VERSION 5.7 ;
BUSBITCHARS "[]" ;
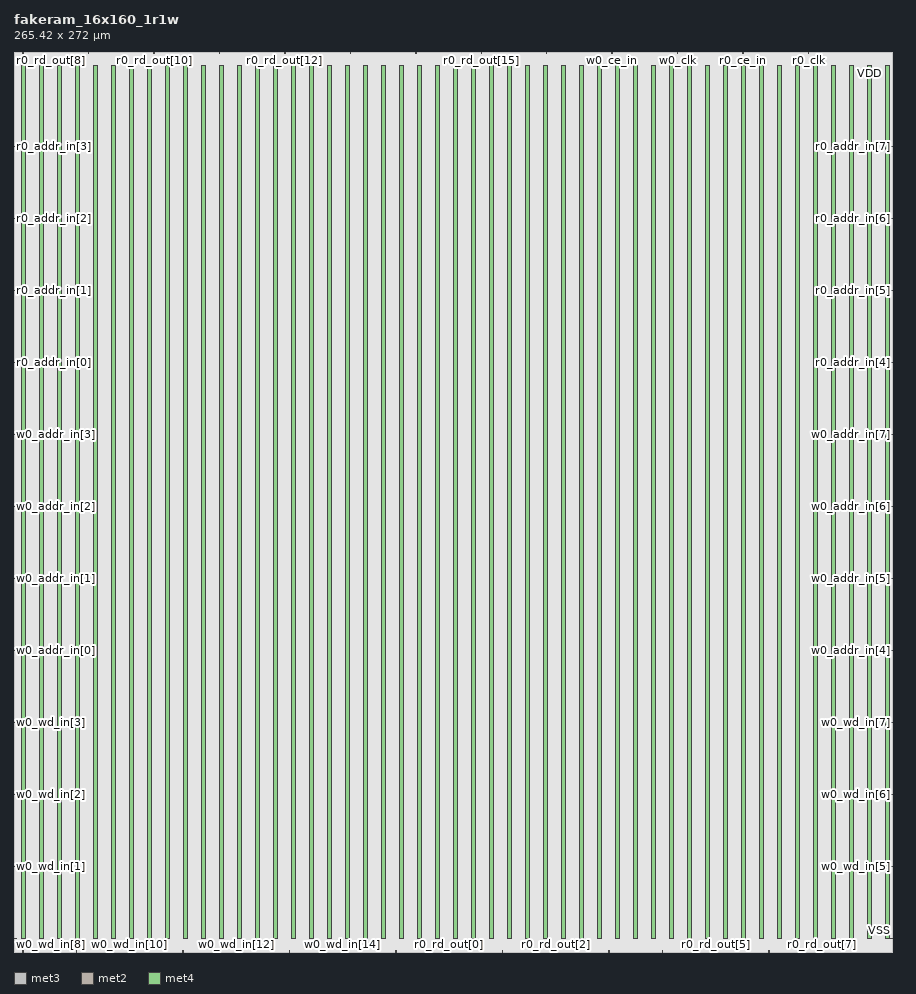
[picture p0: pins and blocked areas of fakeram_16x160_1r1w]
MACRO fakeram_16x160_1r1w
  FOREIGN fakeram_16x160_1r1w 0 0 ;
  SYMMETRY X Y R90 ;
  SIZE 265.420 BY 272.000 ;
  CLASS BLOCK ;
  PIN w0_wd_in[0]
    DIRECTION INPUT ;
    USE SIGNAL ;
    SHAPE ABUTMENT ;
    PORT
      LAYER met3 ;
      RECT 0.000 3.930 0.900 4.230 ;
    END
  END w0_wd_in[0]
  PIN w0_wd_in[1]
    DIRECTION INPUT ;
    USE SIGNAL ;
    SHAPE ABUTMENT ;
    PORT
      LAYER met3 ;
      RECT 0.000 25.690 0.900 25.990 ;
    END
  END w0_wd_in[1]
  PIN w0_wd_in[2]
    DIRECTION INPUT ;
    USE SIGNAL ;
    SHAPE ABUTMENT ;
    PORT
      LAYER met3 ;
      RECT 0.000 47.450 0.900 47.750 ;
    END
  END w0_wd_in[2]
  PIN w0_wd_in[3]
    DIRECTION INPUT ;
    USE SIGNAL ;
    SHAPE ABUTMENT ;
    PORT
      LAYER met3 ;
      RECT 0.000 69.210 0.900 69.510 ;
    END
  END w0_wd_in[3]
  PIN w0_wd_in[4]
    DIRECTION INPUT ;
    USE SIGNAL ;
    SHAPE ABUTMENT ;
    PORT
      LAYER met3 ;
      RECT 264.520 3.930 265.420 4.230 ;
    END
  END w0_wd_in[4]
  PIN w0_wd_in[5]
    DIRECTION INPUT ;
    USE SIGNAL ;
    SHAPE ABUTMENT ;
    PORT
      LAYER met3 ;
      RECT 264.520 25.690 265.420 25.990 ;
    END
  END w0_wd_in[5]
  PIN w0_wd_in[6]
    DIRECTION INPUT ;
    USE SIGNAL ;
    SHAPE ABUTMENT ;
    PORT
      LAYER met3 ;
      RECT 264.520 47.450 265.420 47.750 ;
    END
  END w0_wd_in[6]
  PIN w0_wd_in[7]
    DIRECTION INPUT ;
    USE SIGNAL ;
    SHAPE ABUTMENT ;
    PORT
      LAYER met3 ;
      RECT 264.520 69.210 265.420 69.510 ;
    END
  END w0_wd_in[7]
  PIN w0_wd_in[8]
    DIRECTION INPUT ;
    USE SIGNAL ;
    SHAPE ABUTMENT ;
    PORT
      LAYER met2 ;
      RECT 2.690 0.000 2.830 0.420 ;
    END
  END w0_wd_in[8]
  PIN w0_wd_in[9]
    DIRECTION INPUT ;
    USE SIGNAL ;
    SHAPE ABUTMENT ;
    PORT
      LAYER met2 ;
      RECT 18.790 0.000 18.930 0.420 ;
    END
  END w0_wd_in[9]
  PIN w0_wd_in[10]
    DIRECTION INPUT ;
    USE SIGNAL ;
    SHAPE ABUTMENT ;
    PORT
      LAYER met2 ;
      RECT 34.890 0.000 35.030 0.420 ;
    END
  END w0_wd_in[10]
  PIN w0_wd_in[11]
    DIRECTION INPUT ;
    USE SIGNAL ;
    SHAPE ABUTMENT ;
    PORT
      LAYER met2 ;
      RECT 50.990 0.000 51.130 0.420 ;
    END
  END w0_wd_in[11]
  PIN w0_wd_in[12]
    DIRECTION INPUT ;
    USE SIGNAL ;
    SHAPE ABUTMENT ;
    PORT
      LAYER met2 ;
      RECT 67.090 0.000 67.230 0.420 ;
    END
  END w0_wd_in[12]
  PIN w0_wd_in[13]
    DIRECTION INPUT ;
    USE SIGNAL ;
    SHAPE ABUTMENT ;
    PORT
      LAYER met2 ;
      RECT 83.190 0.000 83.330 0.420 ;
    END
  END w0_wd_in[13]
  PIN w0_wd_in[14]
    DIRECTION INPUT ;
    USE SIGNAL ;
    SHAPE ABUTMENT ;
    PORT
      LAYER met2 ;
      RECT 99.290 0.000 99.430 0.420 ;
    END
  END w0_wd_in[14]
  PIN w0_wd_in[15]
    DIRECTION INPUT ;
    USE SIGNAL ;
    SHAPE ABUTMENT ;
    PORT
      LAYER met2 ;
      RECT 115.390 0.000 115.530 0.420 ;
    END
  END w0_wd_in[15]
  PIN r0_rd_out[0]
    DIRECTION OUTPUT ;
    USE SIGNAL ;
    SHAPE ABUTMENT ;
    PORT
      LAYER met2 ;
      RECT 131.490 0.000 131.630 0.420 ;
    END
  END r0_rd_out[0]
  PIN r0_rd_out[1]
    DIRECTION OUTPUT ;
    USE SIGNAL ;
    SHAPE ABUTMENT ;
    PORT
      LAYER met2 ;
      RECT 147.590 0.000 147.730 0.420 ;
    END
  END r0_rd_out[1]
  PIN r0_rd_out[2]
    DIRECTION OUTPUT ;
    USE SIGNAL ;
    SHAPE ABUTMENT ;
    PORT
      LAYER met2 ;
      RECT 163.690 0.000 163.830 0.420 ;
    END
  END r0_rd_out[2]
  PIN r0_rd_out[3]
    DIRECTION OUTPUT ;
    USE SIGNAL ;
    SHAPE ABUTMENT ;
    PORT
      LAYER met2 ;
      RECT 179.790 0.000 179.930 0.420 ;
    END
  END r0_rd_out[3]
  PIN r0_rd_out[4]
    DIRECTION OUTPUT ;
    USE SIGNAL ;
    SHAPE ABUTMENT ;
    PORT
      LAYER met2 ;
      RECT 195.890 0.000 196.030 0.420 ;
    END
  END r0_rd_out[4]
  PIN r0_rd_out[5]
    DIRECTION OUTPUT ;
    USE SIGNAL ;
    SHAPE ABUTMENT ;
    PORT
      LAYER met2 ;
      RECT 211.990 0.000 212.130 0.420 ;
    END
  END r0_rd_out[5]
  PIN r0_rd_out[6]
    DIRECTION OUTPUT ;
    USE SIGNAL ;
    SHAPE ABUTMENT ;
    PORT
      LAYER met2 ;
      RECT 228.090 0.000 228.230 0.420 ;
    END
  END r0_rd_out[6]
  PIN r0_rd_out[7]
    DIRECTION OUTPUT ;
    USE SIGNAL ;
    SHAPE ABUTMENT ;
    PORT
      LAYER met2 ;
      RECT 244.190 0.000 244.330 0.420 ;
    END
  END r0_rd_out[7]
  PIN r0_rd_out[8]
    DIRECTION OUTPUT ;
    USE SIGNAL ;
    SHAPE ABUTMENT ;
    PORT
      LAYER met2 ;
      RECT 2.690 271.580 2.830 272.000 ;
    END
  END r0_rd_out[8]
  PIN r0_rd_out[9]
    DIRECTION OUTPUT ;
    USE SIGNAL ;
    SHAPE ABUTMENT ;
    PORT
      LAYER met2 ;
      RECT 22.470 271.580 22.610 272.000 ;
    END
  END r0_rd_out[9]
  PIN r0_rd_out[10]
    DIRECTION OUTPUT ;
    USE SIGNAL ;
    SHAPE ABUTMENT ;
    PORT
      LAYER met2 ;
      RECT 42.250 271.580 42.390 272.000 ;
    END
  END r0_rd_out[10]
  PIN r0_rd_out[11]
    DIRECTION OUTPUT ;
    USE SIGNAL ;
    SHAPE ABUTMENT ;
    PORT
      LAYER met2 ;
      RECT 62.030 271.580 62.170 272.000 ;
    END
  END r0_rd_out[11]
  PIN r0_rd_out[12]
    DIRECTION OUTPUT ;
    USE SIGNAL ;
    SHAPE ABUTMENT ;
    PORT
      LAYER met2 ;
      RECT 81.810 271.580 81.950 272.000 ;
    END
  END r0_rd_out[12]
  PIN r0_rd_out[13]
    DIRECTION OUTPUT ;
    USE SIGNAL ;
    SHAPE ABUTMENT ;
    PORT
      LAYER met2 ;
      RECT 101.590 271.580 101.730 272.000 ;
    END
  END r0_rd_out[13]
  PIN r0_rd_out[14]
    DIRECTION OUTPUT ;
    USE SIGNAL ;
    SHAPE ABUTMENT ;
    PORT
      LAYER met2 ;
      RECT 121.370 271.580 121.510 272.000 ;
    END
  END r0_rd_out[14]
  PIN r0_rd_out[15]
    DIRECTION OUTPUT ;
    USE SIGNAL ;
    SHAPE ABUTMENT ;
    PORT
      LAYER met2 ;
      RECT 141.150 271.580 141.290 272.000 ;
    END
  END r0_rd_out[15]
  PIN w0_addr_in[0]
    DIRECTION INPUT ;
    USE SIGNAL ;
    SHAPE ABUTMENT ;
    PORT
      LAYER met3 ;
      RECT 0.000 90.970 0.900 91.270 ;
    END
  END w0_addr_in[0]
  PIN w0_addr_in[1]
    DIRECTION INPUT ;
    USE SIGNAL ;
    SHAPE ABUTMENT ;
    PORT
      LAYER met3 ;
      RECT 0.000 112.730 0.900 113.030 ;
    END
  END w0_addr_in[1]
  PIN w0_addr_in[2]
    DIRECTION INPUT ;
    USE SIGNAL ;
    SHAPE ABUTMENT ;
    PORT
      LAYER met3 ;
      RECT 0.000 134.490 0.900 134.790 ;
    END
  END w0_addr_in[2]
  PIN w0_addr_in[3]
    DIRECTION INPUT ;
    USE SIGNAL ;
    SHAPE ABUTMENT ;
    PORT
      LAYER met3 ;
      RECT 0.000 156.250 0.900 156.550 ;
    END
  END w0_addr_in[3]
  PIN w0_addr_in[4]
    DIRECTION INPUT ;
    USE SIGNAL ;
    SHAPE ABUTMENT ;
    PORT
      LAYER met3 ;
      RECT 264.520 90.970 265.420 91.270 ;
    END
  END w0_addr_in[4]
  PIN w0_addr_in[5]
    DIRECTION INPUT ;
    USE SIGNAL ;
    SHAPE ABUTMENT ;
    PORT
      LAYER met3 ;
      RECT 264.520 112.730 265.420 113.030 ;
    END
  END w0_addr_in[5]
  PIN w0_addr_in[6]
    DIRECTION INPUT ;
    USE SIGNAL ;
    SHAPE ABUTMENT ;
    PORT
      LAYER met3 ;
      RECT 264.520 134.490 265.420 134.790 ;
    END
  END w0_addr_in[6]
  PIN w0_addr_in[7]
    DIRECTION INPUT ;
    USE SIGNAL ;
    SHAPE ABUTMENT ;
    PORT
      LAYER met3 ;
      RECT 264.520 156.250 265.420 156.550 ;
    END
  END w0_addr_in[7]
  PIN r0_addr_in[0]
    DIRECTION INPUT ;
    USE SIGNAL ;
    SHAPE ABUTMENT ;
    PORT
      LAYER met3 ;
      RECT 0.000 178.010 0.900 178.310 ;
    END
  END r0_addr_in[0]
  PIN r0_addr_in[1]
    DIRECTION INPUT ;
    USE SIGNAL ;
    SHAPE ABUTMENT ;
    PORT
      LAYER met3 ;
      RECT 0.000 199.770 0.900 200.070 ;
    END
  END r0_addr_in[1]
  PIN r0_addr_in[2]
    DIRECTION INPUT ;
    USE SIGNAL ;
    SHAPE ABUTMENT ;
    PORT
      LAYER met3 ;
      RECT 0.000 221.530 0.900 221.830 ;
    END
  END r0_addr_in[2]
  PIN r0_addr_in[3]
    DIRECTION INPUT ;
    USE SIGNAL ;
    SHAPE ABUTMENT ;
    PORT
      LAYER met3 ;
      RECT 0.000 243.290 0.900 243.590 ;
    END
  END r0_addr_in[3]
  PIN r0_addr_in[4]
    DIRECTION INPUT ;
    USE SIGNAL ;
    SHAPE ABUTMENT ;
    PORT
      LAYER met3 ;
      RECT 264.520 178.010 265.420 178.310 ;
    END
  END r0_addr_in[4]
  PIN r0_addr_in[5]
    DIRECTION INPUT ;
    USE SIGNAL ;
    SHAPE ABUTMENT ;
    PORT
      LAYER met3 ;
      RECT 264.520 199.770 265.420 200.070 ;
    END
  END r0_addr_in[5]
  PIN r0_addr_in[6]
    DIRECTION INPUT ;
    USE SIGNAL ;
    SHAPE ABUTMENT ;
    PORT
      LAYER met3 ;
      RECT 264.520 221.530 265.420 221.830 ;
    END
  END r0_addr_in[6]
  PIN r0_addr_in[7]
    DIRECTION INPUT ;
    USE SIGNAL ;
    SHAPE ABUTMENT ;
    PORT
      LAYER met3 ;
      RECT 264.520 243.290 265.420 243.590 ;
    END
  END r0_addr_in[7]
  PIN w0_we_in
    DIRECTION INPUT ;
    USE SIGNAL ;
    SHAPE ABUTMENT ;
    PORT
      LAYER met2 ;
      RECT 160.930 271.580 161.070 272.000 ;
    END
  END w0_we_in
  PIN w0_ce_in
    DIRECTION INPUT ;
    USE SIGNAL ;
    SHAPE ABUTMENT ;
    PORT
      LAYER met2 ;
      RECT 180.710 271.580 180.850 272.000 ;
    END
  END w0_ce_in
  PIN w0_clk
    DIRECTION INPUT ;
    USE SIGNAL ;
    SHAPE ABUTMENT ;
    PORT
      LAYER met2 ;
      RECT 200.490 271.580 200.630 272.000 ;
    END
  END w0_clk
  PIN r0_ce_in
    DIRECTION INPUT ;
    USE SIGNAL ;
    SHAPE ABUTMENT ;
    PORT
      LAYER met2 ;
      RECT 220.270 271.580 220.410 272.000 ;
    END
  END r0_ce_in
  PIN r0_clk
    DIRECTION INPUT ;
    USE SIGNAL ;
    SHAPE ABUTMENT ;
    PORT
      LAYER met2 ;
      RECT 240.050 271.580 240.190 272.000 ;
    END
  END r0_clk
  PIN VSS
    DIRECTION INOUT ;
    USE GROUND ;
    PORT
      LAYER met4 ;
      RECT 2.160 4.080 3.360 267.920 ;
      RECT 13.040 4.080 14.240 267.920 ;
      RECT 23.920 4.080 25.120 267.920 ;
      RECT 34.800 4.080 36.000 267.920 ;
      RECT 45.680 4.080 46.880 267.920 ;
      RECT 56.560 4.080 57.760 267.920 ;
      RECT 67.440 4.080 68.640 267.920 ;
      RECT 78.320 4.080 79.520 267.920 ;
      RECT 89.200 4.080 90.400 267.920 ;
      RECT 100.080 4.080 101.280 267.920 ;
      RECT 110.960 4.080 112.160 267.920 ;
      RECT 121.840 4.080 123.040 267.920 ;
      RECT 132.720 4.080 133.920 267.920 ;
      RECT 143.600 4.080 144.800 267.920 ;
      RECT 154.480 4.080 155.680 267.920 ;
      RECT 165.360 4.080 166.560 267.920 ;
      RECT 176.240 4.080 177.440 267.920 ;
      RECT 187.120 4.080 188.320 267.920 ;
      RECT 198.000 4.080 199.200 267.920 ;
      RECT 208.880 4.080 210.080 267.920 ;
      RECT 219.760 4.080 220.960 267.920 ;
      RECT 230.640 4.080 231.840 267.920 ;
      RECT 241.520 4.080 242.720 267.920 ;
      RECT 252.400 4.080 253.600 267.920 ;
      RECT 263.280 4.080 264.480 267.920 ;
    END
  END VSS
  PIN VDD
    DIRECTION INOUT ;
    USE POWER ;
    PORT
      LAYER met4 ;
      RECT 7.600 4.080 8.800 267.920 ;
      RECT 18.480 4.080 19.680 267.920 ;
      RECT 29.360 4.080 30.560 267.920 ;
      RECT 40.240 4.080 41.440 267.920 ;
      RECT 51.120 4.080 52.320 267.920 ;
      RECT 62.000 4.080 63.200 267.920 ;
      RECT 72.880 4.080 74.080 267.920 ;
      RECT 83.760 4.080 84.960 267.920 ;
      RECT 94.640 4.080 95.840 267.920 ;
      RECT 105.520 4.080 106.720 267.920 ;
      RECT 116.400 4.080 117.600 267.920 ;
      RECT 127.280 4.080 128.480 267.920 ;
      RECT 138.160 4.080 139.360 267.920 ;
      RECT 149.040 4.080 150.240 267.920 ;
      RECT 159.920 4.080 161.120 267.920 ;
      RECT 170.800 4.080 172.000 267.920 ;
      RECT 181.680 4.080 182.880 267.920 ;
      RECT 192.560 4.080 193.760 267.920 ;
      RECT 203.440 4.080 204.640 267.920 ;
      RECT 214.320 4.080 215.520 267.920 ;
      RECT 225.200 4.080 226.400 267.920 ;
      RECT 236.080 4.080 237.280 267.920 ;
      RECT 246.960 4.080 248.160 267.920 ;
      RECT 257.840 4.080 259.040 267.920 ;
    END
  END VDD
  OBS
    LAYER met1 ;
    RECT 0 0 265.420 272.000 ;
    LAYER met2 ;
    RECT 0 0 265.420 272.000 ;
    LAYER met3 ;
    RECT 0 0 265.420 272.000 ;
    LAYER met4 ;
    RECT 0 0 265.420 272.000 ;
  END
END fakeram_16x160_1r1w

END LIBRARY
